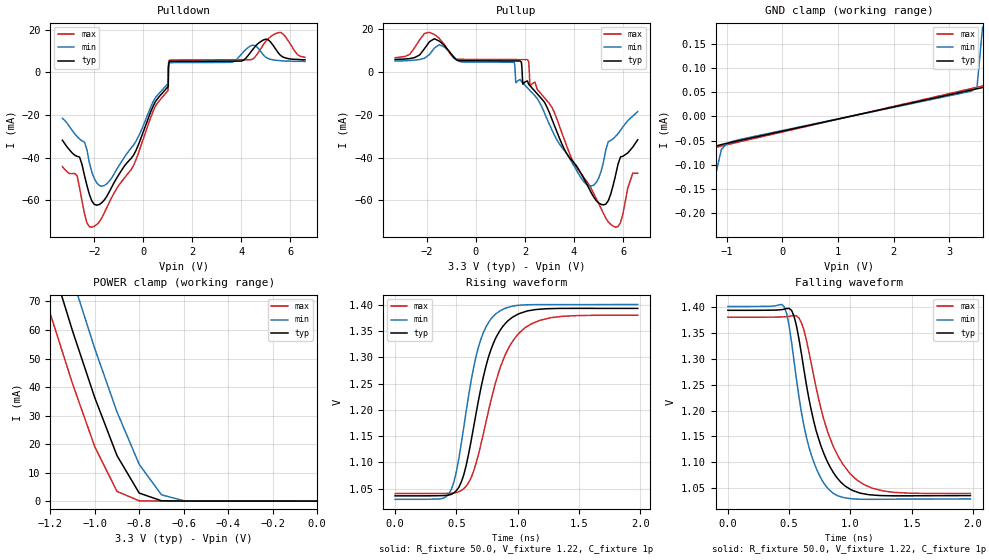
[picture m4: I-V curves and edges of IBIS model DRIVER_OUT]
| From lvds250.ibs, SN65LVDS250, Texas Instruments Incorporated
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|   Driver Output Model
[Model]   DRIVER_OUT
Model_type   3-state
| Signals   1Y,1Z,2Y,2Z,3Y,3Z,4Y,4Z
Vmeas = 1.22V   |Reference voltage for timing measurements
Cref = 1pF   |Timing specification test load capacitance value
Rref = 50   |Note: 50 Ohm load; single ended configuration
Vref = 1.22V   |Timing specification test load voltage
| variable   typ   min   max
C_comp   2.11pF   2.05pF   2.36pF
|   typ   min   max
[Temperature Range]   25.0   85   -40
[Voltage range]   3.3V   3.0V   3.6V
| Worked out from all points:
|   slope of the pulldown table from 0 to 0.495 V, typ, clamps not added: 34.9 ohm
|   slope of the pullup table from 0 to 0.495 V, typ, clamps not added: 25 kohm
|   GND clamp passes 1 mA (typ) near -1.61 V on its own axis
|   POWER clamp passes 1 mA (typ) near -0.73 V on its own axis
|   rising waveform, R_fixture 50.0, V_fixture 1.22, C_fixture 1p: 20-80 % time 202ps typ, 172ps min, 242ps max; typ from 1.04 V to 1.39 V
|   falling waveform, R_fixture 50.0, V_fixture 1.22, C_fixture 1p: 20-80 % time 209ps typ, 174ps min, 247ps max; typ from 1.39 V to 1.04 V
[GND_clamp]
|   Voltage   I(typ)   I(min)   I(max)
-3.6V     -101mA     -111mA     -91.7mA
-1.7V     -1.99mA    -5.02mA    -245uA
-1.6V     -887uA     -3.16mA    -91.9uA
-1.5V     -293uA     -1.77mA    -73.3uA
-1.4V     -106uA     -814uA     -69.3uA
-1.3V     -69.2uA    -305uA     -66.5uA
-1.2V     -61.5uA    -119uA     -63.9uA
-1.1V     -58.2uA    -68.9uA    -61.2uA
-1V       -55.6uA    -56.1uA    -58.6uA
3.4V      54.5uA     52.3uA     57.5uA
3.5V      57uA       59.6uA     60.2uA
3.6V      59.5uA     184uA      62.8uA
[Power_clamp]
| Note that the[POWER_clamp]voltage table is referenced to Vcc
| and is calculated using Vtable=Vcc - Vmeasured.
|   Voltage   I(typ)   I(min)   I(max)
-3.3V     812mA      831mA      791mA
-1.3V     112mA      131mA      91.8mA
-1.2V     84.9mA     104mA      65.7mA
-1.1V     59.7mA     77.9mA     41.2mA
-1V       36.3mA     53.5mA     19.1mA
-900mV    16mA       31.3mA     3.46mA
-800mV    2.86mA     12.9mA     140uA
-700mV    170uA      2.27mA     81.7uA
-600mV    69.2uA     184uA      78.6uA
0V        52uA       42.5uA     62.8uA
[Pulldown]
|   Voltage   I(typ)   I(min)   I(max)
-3.3V     -31.8mA    -21.5mA    -44.2mA
-2.7V     -39.4mA    -30.1mA    -48.5mA
-2.2V     -57.2mA    -42.3mA    -72.4mA
-1.7V     -61.2mA    -53.4mA    -68.4mA
1.01V     -6.69mA    -5.22mA    -8.49mA
1.02V     -6.56mA    -5.1mA     2.15mA
1.03V     2.6mA      2.15mA     3.84mA
1.06V     4.83mA     4.16mA     5.66mA
4.4V      9.74mA     12.6mA     5.98mA
5V        15.6mA     7.1mA      14.6mA
5.6V      8mA        5.5mA      18.8mA
6.6V      5.9mA      5.1mA      7.1mA
[Pullup]
|   Voltage   I(typ)   I(min)   I(max)
| Note that the[Pullup]voltage table is referenced to Vcc
| and is calculated using Vtable=Vcc - Vmeasured.
-3.3V     5.9mA      5.2mA      6.7mA
-1.7V     15.6mA     11.2mA     17.6mA
-800mV    5.73mA     5.96mA     5.98mA
1.56V     5.2mA      4.61mA     5.85mA
1.63V     5.2mA      -4.97mA    5.85mA
2.1V      -4.14mA    -7.41mA    5.82mA
2.21V     -6.47mA    -8.74mA    -6.44mA
3.1V      -22.1mA    -27.1mA    -16.5mA
4.6V      -54.2mA    -53.1mA    -52.5mA
5.3V      -61.8mA    -36.3mA    -68.4mA
5.7V      -48.1mA    -30.1mA    -72.6mA
6.6V      -31.7mA    -18.5mA    -47.4mA
[Ramp]
|   typ   min   max
dV/dt_r   0.200/184ps   0.200/151ps   0.200/236ps
dV/dt_f   0.200/190ps   0.200/148ps   0.200/238ps
R_load = 50ohm | Note: The measurement is on a differential configuration
|   with 100ohm line-to-line and 1p
[Rising Waveform]
R_fixture = 50.0
V_fixture = 1.22
C_fixture = 1p
L_fixture = 0n
|   V(typ)   V(min)   V(max)
0s        1.036V     1.029V     1.04V
440ps     1.038V     1.04V      1.041V
480ps     1.042V     1.063V     1.042V
540ps     1.062V     1.136V     1.046V
620ps     1.141V     1.255V     1.07V
700ps     1.241V     1.334V     1.134V
820ps     1.336V     1.382V     1.252V
940ps     1.373V     1.396V     1.324V
1.12ns    1.39V      1.4V       1.365V
1.98ns    1.393V     1.401V     1.38V
[Falling Waveform]
R_fixture = 50.0
V_fixture = 1.22
C_fixture = 1p
L_fixture = 0n
|   V(typ)   V(min)   V(max)
0s        1.394V     1.401V     1.38V
460ps     1.396V     1.4V       1.381V
540ps     1.382V     1.296V     1.384V
600ps     1.31V      1.197V     1.37V
660ps     1.225V     1.131V     1.315V
760ps     1.131V     1.069V     1.204V
860ps     1.081V     1.04V      1.131V
1ns       1.048V     1.03V      1.078V
1.18ns    1.037V     1.029V     1.05V
1.98ns    1.036V     1.029V     1.04V
